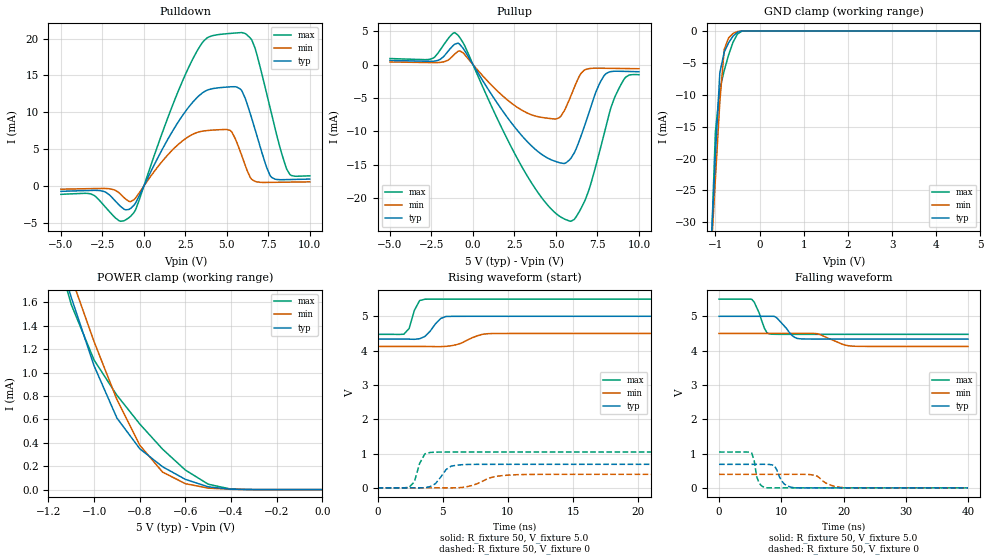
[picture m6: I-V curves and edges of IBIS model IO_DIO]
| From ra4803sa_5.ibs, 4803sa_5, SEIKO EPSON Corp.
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[Model]   IO_DIO
Model_type I/O
Enable Active-High
Polarity Non-Inverting
Vinh=4.0
Vinl=1.0
Vmeas=2.50
C_comp   5p   4p   6p
[Temperature Range] 25   85   -40
[Voltage Range]   5.0   4.5   5.5
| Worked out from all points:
|   slope of the pulldown table from 0 to 0.75 V, typ, clamps not added: 219 ohm
|   slope of the pullup table from 0 to 0.75 V, typ, clamps not added: 247 ohm
|   GND clamp passes 1 mA (typ) near -0.62 V on its own axis
|   POWER clamp passes 1 mA (typ) near -0.99 V on its own axis
|   falling waveform, R_fixture 50, V_fixture 5.0: 20-80 % time 1.86ns typ, 2.92ns min, 1.28ns max; typ from 5 V to 4.34 V
|   falling waveform, R_fixture 50, V_fixture 0: 20-80 % time 1.17ns typ, 1.99ns min, 726ps max; typ from 0.685 V to 0 V
|   rising waveform, R_fixture 50, V_fixture 5.0: 20-80 % time 886ps typ, 1.35ns min, 549ps max; typ from 4.34 V to 5 V
|   rising waveform, R_fixture 50, V_fixture 0: 20-80 % time 845ps typ, 1.53ns min, 555ps max; typ from 0 V to 0.685 V
[Pullup]
-5V       625.9uA    391.4uA    902.1uA
-2.6V     486.1uA    298uA      782.3uA
-1.2V     2.823mA    1.318mA    4.674mA
-900mV    3.207mA    1.98mA     4.392mA
3.5V      -12.08mA   -7.484mA   -17.57mA
5.2V      -14.65mA   -7.939mA   -22.64mA
5.9V      -14.01mA   -4.694mA   -23.42mA
6.8V      -8.609mA   -732.2uA   -20.01mA
7.9V      -1.66mA    -554.4uA   -10.39mA
8.5V      -1.001mA   -572.6uA   -5.143mA
9.1V      -1.018mA   -592.1uA   -2.2mA
10V       -1.071mA   -623.9uA   -1.515mA
[Pulldown]
-5V       -725.4uA   -436.8uA   -1.134mA
-2.6V     -639.4uA   -337.7uA   -2.15mA
-1.5V     -2.56mA    -915.6uA   -4.704mA
-800mV    -3.04mA    -2.118mA   -4.113mA
3.2V      11.98mA    7.253mA    18.29mA
3.9V      13.06mA    7.537mA    20.2mA
5.5V      13.46mA    6.445mA    20.74mA
5.9V      12.92mA    4.1mA      20.8mA
6.5V      9.144mA    890.6uA    19.81mA
7.6V      1.431mA    490.4uA    10.65mA
8.6V      864.8uA    518.2uA    2.299mA
10V       937.6uA    562.8uA    1.38mA
[GND Clamp]
-5V       -674.1mA   -554.3mA   -855.6mA
-1.1V     -34.38mA   -35.36mA   -35.33mA
-1V       -19.42mA   -23.16mA   -15.8mA
-900mV    -6.562mA   -11.13mA   -9.129mA
-800mV    -3.309mA   -2.897mA   -6.201mA
-700mV    -1.841mA   -1.087mA   -3.742mA
-600mV    -807.8uA   -397.8uA   -1.764mA
-500mV    -207.4uA   -91.02uA   -476.4uA
-400mV    -22.76uA   -11uA      -42.64uA
-300mV    -1.222uA   -843.7nA   -1.241uA
5V        108pA      12.81uA    75.94pA
[POWER Clamp]
-5V       33.83mA    29.42mA    41.07mA
-1.2V     2.299mA    2.403mA    2.272mA
-1.1V     1.642mA    1.816mA    1.581mA
-1V       1.058mA    1.264mA    1.108mA
-900mV    611.8uA    769.8uA    806.6uA
-800mV    349.6uA    380.1uA    561.1uA
-700mV    195.4uA    149.6uA    345.8uA
-600mV    87.51uA    50.63uA    167uA
-500mV    23.8uA     12.81uA    46.11uA
-400mV    3.184uA    2.198uA    4.195uA
0V        108pA      202.4pA    89.13pA
[Falling Waveform]
R_fixture=50
V_fixture=5.0
V_fixture_min=4.5
V_fixture_max=5.5
0s        5V         4.5V       5.5V
5.253ns   5V         4.5V       5.497V
7.273ns   5V         4.5V       4.66V
8.081ns   5V         4.5V       4.488V
9.293ns   4.954V     4.5V       4.475V
11.72ns   4.444V     4.5V       4.474V
12.93ns   4.345V     4.5V       4.474V
15.76ns   4.337V     4.494V     4.474V
21.41ns   4.336V     4.13V      4.474V
40ns      4.336V     4.121V     4.474V
[Falling Waveform]
R_fixture=50
V_fixture=0
V_fixture_min=0
V_fixture_max=0
0s        685.4mV    393.9mV    1.044V
5.253ns   685.5mV    393.9mV    1.018V
6.465ns   686.1mV    393.9mV    132.1mV
7.677ns   685.5mV    393.9mV    1.973mV
8.889ns   647.5mV    394mV      17.87uV
10.1ns    192.5mV    394.2mV    -5.628uV
11.72ns   12.4mV     394.8mV    1.262uV
15.35ns   18.33uV    367.4mV    4.653uV
20.2ns    8.415uV    4.402mV    -876.9nV
40ns      13.58uV    -19.03uV   -4.895uV
[Rising Waveform]
R_fixture=50
V_fixture=5.0
V_fixture_min=4.5
V_fixture_max=5.5
0s        4.336V     4.121V     4.474V
2.02ns    4.337V     4.121V     4.478V
2.424ns   4.334V     4.121V     4.644V
2.828ns   4.329V     4.121V     5.173V
3.232ns   4.346V     4.121V     5.458V
3.636ns   4.412V     4.121V     5.497V
4.848ns   4.936V     4.116V     5.5V
5.253ns   4.994V     4.123V     5.5V
8.889ns   5V         4.498V     5.5V
40ns      5V         4.5V       5.5V
[Rising Waveform]
R_fixture=50
V_fixture=0
V_fixture_min=0
V_fixture_max=0
0s        0V         0V         0V
2.424ns   74.68uV    -2.974uV   15.57mV
2.828ns   50.74uV    -1.556uV   173.2mV
3.232ns   -637.1uV   4.424uV    711.9mV
3.636ns   2.294mV    29.66uV    991.6mV
4.04ns    37.19mV    75.23uV    1.031V
5.253ns   529.9mV    -429.6uV   1.044V
6.465ns   673.7mV    9.785mV    1.044V
10.91ns   685.4mV    385.1mV    1.044V
40ns      685.4mV    393.9mV    1.044V
[Ramp]
R_load=50
dV/dt_r   4.112E-1/8.188E-10   2.364E-1/1.520E-9   6.263E-1/4.389E-10
dV/dt_f   3.981E-1/1.864E-9   2.272E-1/2.903E-9   6.157E-1/1.283E-9
|[End   IO_DIO
